VERSION 5.8 ;
# Educational scaled dummy bump for FlowLab GCD (~88.8 µm die).
# Derived from OpenROAD test/Nangate45_io/dummy_pads.lef (BSD-3).
# Not a JEDEC C4 / µbump. SIZE is scaled so the configured 4×4 array fits the die.
# PIN PAD is on metal10 (OpenROAD rdl_route lab) and metal6 (GCD pin layer).

UNITS
  DATABASE MICRONS 2000 ;
END UNITS

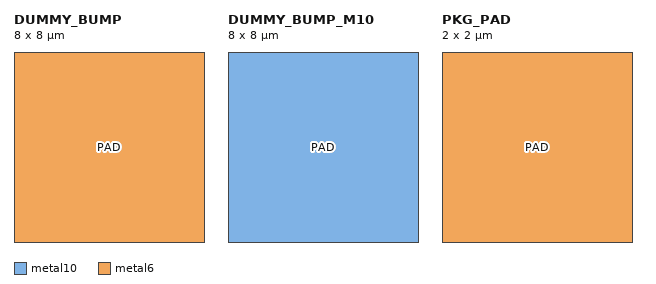
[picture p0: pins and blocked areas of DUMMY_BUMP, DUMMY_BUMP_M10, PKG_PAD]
MACRO DUMMY_BUMP
  CLASS COVER BUMP ;
  ORIGIN 0 0 ;
  SIZE 8 BY 8 ;
  SYMMETRY X Y R90 ;
  PIN PAD
    DIRECTION INOUT ;
    PORT
      LAYER metal10 ;
        RECT 0.0 0.0 8.0 8.0 ;
      LAYER metal6 ;
        RECT 0.0 0.0 8.0 8.0 ;
    END
  END PAD
END DUMMY_BUMP

MACRO DUMMY_BUMP_M10
  CLASS COVER BUMP ;
  ORIGIN 0 0 ;
  SIZE 8 BY 8 ;
  SYMMETRY X Y R90 ;
  PIN PAD
    DIRECTION INOUT ;
    PORT
      LAYER metal10 ;
        RECT 0.0 0.0 8.0 8.0 ;
    END
  END PAD
END DUMMY_BUMP_M10

MACRO PKG_PAD
  CLASS CORE ;
  ORIGIN 0 0 ;
  SIZE 2 BY 2 ;
  SYMMETRY X Y R90 ;
  PIN PAD
    DIRECTION INOUT ;
    PORT
      LAYER metal10 ;
        RECT 0.0 0.0 2.0 2.0 ;
      LAYER metal6 ;
        RECT 0.0 0.0 2.0 2.0 ;
    END
  END PAD
END PKG_PAD
